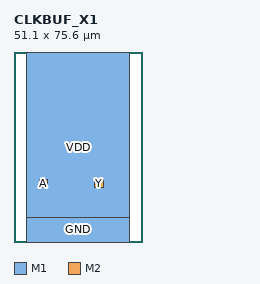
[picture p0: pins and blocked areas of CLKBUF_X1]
MACRO CLKBUF_X1
  CLASS CORE ;
  ORIGIN 0 0 ;
  SIZE 51.100 BY 75.600 ;
  SYMMETRY X Y ;
  SITE TR1um_access_site ;
  PIN VDD
    DIRECTION INOUT ;
    USE POWER ;
    PORT
      LAYER M1 ;
        RECT 5.000 0.000 46.100 75.600 ;
    END
  END VDD
  PIN GND
    DIRECTION INOUT ;
    USE GROUND ;
    PORT
      LAYER M1 ;
        RECT 5.000 0.000 46.100 9.800 ;
    END
  END GND
  PIN A
    DIRECTION INPUT ;
    USE SIGNAL ;
    PORT
      LAYER M2 ;
        RECT 10.100 21.600 13.500 25.000 ;
    END
  END A
  PIN Y
    DIRECTION OUTPUT ;
    USE SIGNAL ;
    PORT
      LAYER M2 ;
        RECT 32.100 21.600 35.500 25.000 ;
    END
  END Y
  OBS
    LAYER M1 ;
      RECT 21.100 6.400 24.650 14.400 ;
    LAYER M1 ;
      RECT 10.100 16.400 15.700 34.400 ;
    LAYER M1 ;
      RECT 26.450 16.400 29.700 34.400 ;
    LAYER M1 ;
      RECT 13.100 6.400 24.650 51.200 ;
    LAYER M1 ;
      RECT 21.100 36.400 24.650 51.200 ;
    LAYER M1 ;
      RECT 26.450 6.400 39.700 51.200 ;
    LAYER V1 ;
      RECT 11.100 22.600 12.500 24.000 ;
    LAYER V1 ;
      RECT 33.100 22.600 34.500 24.000 ;
  END
END CLKBUF_X1
